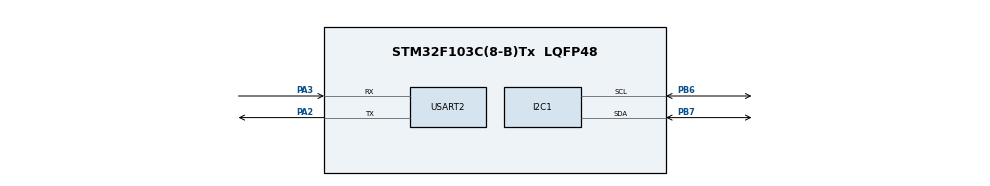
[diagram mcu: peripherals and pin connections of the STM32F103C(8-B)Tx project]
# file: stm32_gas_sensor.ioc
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Mcu.Family=STM32F1
Mcu.Name=STM32F103C(8-B)Tx
Mcu.Package=LQFP48
NVIC.PriorityGroup=NVIC_PRIORITYGROUP_4
PA13.Mode=Serial_Wire
PA13.Signal=SYS_JTMS-SWDIO
PA14.Mode=Serial_Wire
PA14.Signal=SYS_JTCK-SWCLK
PA2.Mode=Asynchronous
PA2.Signal=USART2_TX
PA3.Mode=Asynchronous
PA3.Signal=USART2_RX
PB6.Mode=I2C
PB6.Signal=I2C1_SCL
PB7.Mode=I2C
PB7.Signal=I2C1_SDA
PD0-OSC_IN.Mode=HSE-External-Oscillator
PD0-OSC_IN.Signal=RCC_OSC_IN
PD1-OSC_OUT.Mode=HSE-External-Oscillator
PD1-OSC_OUT.Signal=RCC_OSC_OUT
ProjectManager.HeapSize=0x200
ProjectManager.StackSize=0x400
ProjectManager.TargetToolchain=STM32CubeIDE
RCC.AHBFreq_Value=72000000
RCC.APB1CLKDivider=RCC_HCLK_DIV2
RCC.APB1Freq_Value=36000000
RCC.APB1TimFreq_Value=72000000
RCC.APB2Freq_Value=72000000
RCC.APB2TimFreq_Value=72000000
RCC.HCLKFreq_Value=72000000
RCC.PLLMUL=RCC_PLL_MUL9
RCC.PLLSourceVirtual=RCC_PLLSOURCE_HSE
RCC.SYSCLKFreq_VALUE=72000000
RCC.SYSCLKSource=RCC_SYSCLKSOURCE_PLLCLK
RCC.USBFreq_Value=72000000
USART2.VirtualMode=VM_ASYNC
board=custom

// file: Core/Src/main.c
/* USER CODE BEGIN Header */
/**
 ******************************************************************************
 * @file           : main.c
 * @brief          : Main program body
 ******************************************************************************
 * @attention
 *
 * Copyright (c) 2022 STMicroelectronics.
 * All rights reserved.
 *
 * This software is licensed under terms that can be found in the LICENSE file
 * in the root directory of this software component.
 * If no LICENSE file comes with this software, it is provided AS-IS.
 *
 ******************************************************************************
 */
/* USER CODE END Header */
#include "main.h"

/* USER CODE BEGIN Includes */
#include "lcd16x2_i2c.h"
/* USER CODE END Includes */

I2C_HandleTypeDef hi2c1;

UART_HandleTypeDef huart2;

void SystemClock_Config(void);
static void MX_GPIO_Init(void);
static void MX_USART2_UART_Init(void);
static void MX_I2C1_Init(void);

int main(void)
{

  /* MCU Configuration--------------------------------------------------------*/

  /* Reset of all peripherals, Initializes the Flash interface and the Systick. */
  HAL_Init();

  /* Configure the system clock */
  SystemClock_Config();

  /* Initialize all configured peripherals */
  MX_GPIO_Init();
  MX_USART2_UART_Init();
  MX_I2C1_Init();
  /* USER CODE BEGIN 2 */
  lcd16x2_i2c_init(&hi2c1);
  /* USER CODE END 2 */

  /* Infinite loop */
	while (1)
	{

	}
}

void SystemClock_Config(void)
{
  RCC_OscInitTypeDef RCC_OscInitStruct = {0};
  RCC_ClkInitTypeDef RCC_ClkInitStruct = {0};

  /** Initializes the RCC Oscillators according to the specified parameters
  * in the RCC_OscInitTypeDef structure.
  */
  RCC_OscInitStruct.OscillatorType = RCC_OSCILLATORTYPE_HSE;
  RCC_OscInitStruct.HSEState = RCC_HSE_ON;
  RCC_OscInitStruct.HSEPredivValue = RCC_HSE_PREDIV_DIV1;
  RCC_OscInitStruct.HSIState = RCC_HSI_ON;
  RCC_OscInitStruct.PLL.PLLState = RCC_PLL_ON;
  RCC_OscInitStruct.PLL.PLLSource = RCC_PLLSOURCE_HSE;
  RCC_OscInitStruct.PLL.PLLMUL = RCC_PLL_MUL6;
  if (HAL_RCC_OscConfig(&RCC_OscInitStruct) != HAL_OK)
  {
    Error_Handler();
  }

  /** Initializes the CPU, AHB and APB buses clocks
  */
  RCC_ClkInitStruct.ClockType = RCC_CLOCKTYPE_HCLK|RCC_CLOCKTYPE_SYSCLK
                              |RCC_CLOCKTYPE_PCLK1|RCC_CLOCKTYPE_PCLK2;
  RCC_ClkInitStruct.SYSCLKSource = RCC_SYSCLKSOURCE_PLLCLK;
  RCC_ClkInitStruct.AHBCLKDivider = RCC_SYSCLK_DIV1;
  RCC_ClkInitStruct.APB1CLKDivider = RCC_HCLK_DIV2;
  RCC_ClkInitStruct.APB2CLKDivider = RCC_HCLK_DIV1;

  if (HAL_RCC_ClockConfig(&RCC_ClkInitStruct, FLASH_LATENCY_1) != HAL_OK)
  {
    Error_Handler();
  }
}

static void MX_I2C1_Init(void)
{

  hi2c1.Instance = I2C1;
  hi2c1.Init.ClockSpeed = 100000;
  hi2c1.Init.DutyCycle = I2C_DUTYCYCLE_2;
  hi2c1.Init.OwnAddress1 = 0;
  hi2c1.Init.AddressingMode = I2C_ADDRESSINGMODE_7BIT;
  hi2c1.Init.DualAddressMode = I2C_DUALADDRESS_DISABLE;
  hi2c1.Init.OwnAddress2 = 0;
  hi2c1.Init.GeneralCallMode = I2C_GENERALCALL_DISABLE;
  hi2c1.Init.NoStretchMode = I2C_NOSTRETCH_DISABLE;
  if (HAL_I2C_Init(&hi2c1) != HAL_OK)
  {
    Error_Handler();
  }

}

static void MX_USART2_UART_Init(void)
{

  huart2.Instance = USART2;
  huart2.Init.BaudRate = 115200;
  huart2.Init.WordLength = UART_WORDLENGTH_8B;
  huart2.Init.StopBits = UART_STOPBITS_1;
  huart2.Init.Parity = UART_PARITY_NONE;
  huart2.Init.Mode = UART_MODE_TX_RX;
  huart2.Init.HwFlowCtl = UART_HWCONTROL_NONE;
  huart2.Init.OverSampling = UART_OVERSAMPLING_16;
  if (HAL_UART_Init(&huart2) != HAL_OK)
  {
    Error_Handler();
  }

}

static void MX_GPIO_Init(void)
{

  /* GPIO Ports Clock Enable */
  __HAL_RCC_GPIOD_CLK_ENABLE();
  __HAL_RCC_GPIOA_CLK_ENABLE();
  __HAL_RCC_GPIOB_CLK_ENABLE();

}

void Error_Handler(void)
{
	__disable_irq();
	while (1)
	{
	}
}
